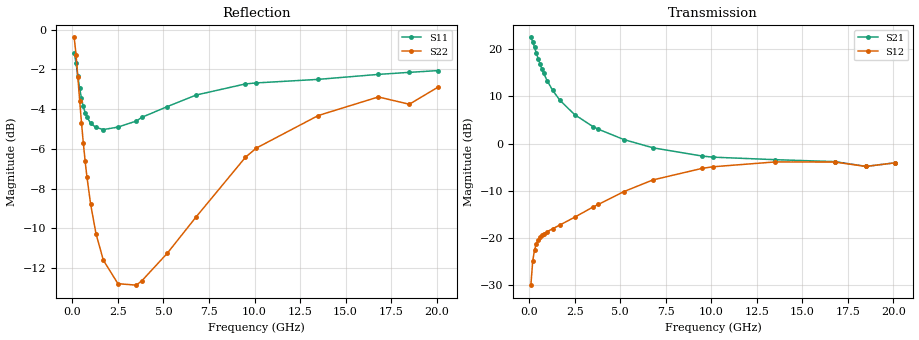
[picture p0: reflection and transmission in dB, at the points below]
!  Infineon Technologies AG
! BFR380L3 , PF131585-7, No.6, Th 09.10.01, soldered on pcb-board, measured with PP GSG850
!  Vce=1.75 V,  Ic=4.0 mA
! Common Emitter S-Parameters:  15. November 2001
#  GHz  S  MA  R  50
! f  S11  S21  S12  S22
! GHz  Mag  Ang  Mag  Ang  Mag  Ang  Mag  Ang
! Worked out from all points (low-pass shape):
!   201 points, 100 MHz to 20.1 GHz, reference 50 ohm
!   highest |S21| = 22.47 dB at 100 MHz (marker M1); lowest = -4.8 dB at 18.5 GHz (marker M2)
!   |S21| within 3 dB of the highest: start of sweep to 373.4 MHz
!   lowest |S11| = -5.0 dB at 1.7 GHz (marker M3), VSWR 3.55, Z = 14.1 - j3.01 ohm
!   |S11| at or under -10 dB: nowhere
!   |S22| runs from -13.0 to -0.4 dB; largest |S21 - S12| = 13
!   S11 on the Smith chart (normalised r, x): 100 MHz: 1.13, -3.83; 400 MHz: 0.34, -0.98; 1 GHz: 0.29, -0.30; 3.8 GHz: 0.27, +0.31; 9.5 GHz: 0.35, +1.10; 20.1 GHz: 0.98, +2.55
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0.1  0.8751 -27.1  13.28 162.3  0.03173 73.9  0.9565 -16.1
0.2  0.8255 -50.7  11.9 147.0  0.05663 63.7  0.8654 -30.0
0.3  0.7635 -71.3  10.43 134.6  0.07495 55.0  0.7595 -40.9
0.4  0.7119 -87.7  9.059 124.7  0.08697 48.7  0.6633 -49.1
0.5  0.6721 -101.5  7.898 116.9  0.09534 44.4  0.5838 -55.3
0.6  0.641 -112.8  6.949 110.7  0.1016 41.7  0.5191 -60.2
0.7  0.6189 -122.5  6.186 105.3  0.1064 39.7  0.4674 -64.1
0.8  0.6035 -130.4  5.551 100.8  0.1101 38.6  0.426 -67.3
1  0.5813 -143.5  4.596 93.4  0.1168 37.6  0.3646 -72.4
1.3  0.5678 -158.2  3.646 84.5  0.1255 37.9  0.3063 -78.5
1.7  0.5609 -172.5  2.862 74.9  0.1375 39.7  0.2632 -85.4
2.5  0.5688 167.0  2.024 59.6  0.1659 44.0  0.2297 -99.0
3.5  0.5889 148.1  1.514 44.0  0.2122 47.0  0.2278 -117.2
3.8  0.6016 143.5  1.419 40.1  0.2265 47.2  0.2332 -124.1
5.2  0.6403 123.8  1.102 23.6  0.3095 44.0  0.2736 -149.9
6.8  0.6851 104.7  0.9012 9.9  0.4118 36.0  0.3384 -179.6
9.5  0.7305 81.4  0.7368 -4.8  0.5455 17.5  0.4775 142.7
10.1  0.7348 77.0  0.7172 -7.3  0.5676 13.3  0.5038 135.1
13.5  0.75 59.1  0.6748 -20.7  0.6382 -9.3  0.6083 101.4
16.8  0.772 47.2  0.6432 -32.2  0.6365 -25.9  0.6774 78.0
18.5  0.7811 45.4  0.5731 -39.7  0.5719 -34.5  0.6494 72.0
20.1  0.7893 38.3  0.6255 -43.4  0.6246 -39.6  0.7181 61.1
